VERSION 5.7 ;
  NOWIREEXTENSIONATPIN ON ;
  DIVIDERCHAR "/" ;
  BUSBITCHARS "[]" ;
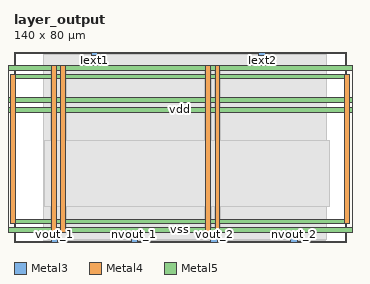
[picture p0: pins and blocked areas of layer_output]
MACRO layer_output
  CLASS BLOCK ;
  FOREIGN layer_output ;
  ORIGIN 0.000 0.000 ;
  SIZE 140.000 BY 80.000 ;
  PIN Iext1
    DIRECTION INPUT ;
    USE SIGNAL ;
    ANTENNAGATEAREA 0.280000 ;
    ANTENNADIFFAREA 1.380000 ;
    PORT
      LAYER Metal3 ;
        RECT 32.480 78.500 35.280 80.000 ;
    END
  END Iext1
  PIN Iext2
    DIRECTION INPUT ;
    USE SIGNAL ;
    ANTENNAGATEAREA 0.280000 ;
    ANTENNADIFFAREA 1.380000 ;
    PORT
      LAYER Metal3 ;
        RECT 103.040 78.500 105.840 80.000 ;
    END
  END Iext2
  PIN nvout_1
    DIRECTION OUTPUT ;
    USE SIGNAL ;
    ANTENNAGATEAREA 0.560000 ;
    ANTENNADIFFAREA 0.750000 ;
    PORT
      LAYER Metal3 ;
        RECT 49.280 0.000 52.080 1.500 ;
    END
  END nvout_1
  PIN nvout_2
    DIRECTION OUTPUT ;
    USE SIGNAL ;
    ANTENNAGATEAREA 0.560000 ;
    ANTENNADIFFAREA 0.750000 ;
    PORT
      LAYER Metal3 ;
        RECT 116.480 0.000 119.280 1.500 ;
    END
  END nvout_2
  PIN vdd
    DIRECTION INOUT ;
    USE POWER ;
    PORT
      LAYER Metal4 ;
        RECT -1.280 7.680 0.720 70.720 ;
    END
    PORT
      LAYER Metal4 ;
        RECT 139.280 7.680 141.280 70.720 ;
    END
    PORT
      LAYER Metal5 ;
        RECT -1.280 7.680 141.280 9.680 ;
    END
    PORT
      LAYER Metal5 ;
        RECT -1.280 68.720 141.280 70.720 ;
    END
    PORT
      LAYER Metal4 ;
        RECT 15.720 4.180 17.720 74.220 ;
    END
    PORT
      LAYER Metal4 ;
        RECT 80.720 4.180 82.720 74.220 ;
    END
    PORT
      LAYER Metal5 ;
        RECT -4.780 54.680 144.780 56.680 ;
    END
  END vdd
  PIN vout_1
    DIRECTION OUTPUT ;
    USE SIGNAL ;
    ANTENNADIFFAREA 0.750000 ;
    PORT
      LAYER Metal3 ;
        RECT 15.680 0.000 18.480 1.500 ;
    END
  END vout_1
  PIN vout_2
    DIRECTION OUTPUT ;
    USE SIGNAL ;
    ANTENNADIFFAREA 0.750000 ;
    PORT
      LAYER Metal3 ;
        RECT 82.880 0.000 85.680 1.500 ;
    END
  END vout_2
  PIN vss
    DIRECTION INOUT ;
    USE GROUND ;
    PORT
      LAYER Metal4 ;
        RECT -4.780 4.180 -2.780 74.220 ;
    END
    PORT
      LAYER Metal4 ;
        RECT 142.780 4.180 144.780 74.220 ;
    END
    PORT
      LAYER Metal5 ;
        RECT -4.780 4.180 144.780 6.180 ;
    END
    PORT
      LAYER Metal5 ;
        RECT -4.780 72.220 144.780 74.220 ;
    END
    PORT
      LAYER Metal4 ;
        RECT 19.720 4.180 21.720 74.220 ;
    END
    PORT
      LAYER Metal4 ;
        RECT 84.720 4.180 86.720 74.220 ;
    END
    PORT
      LAYER Metal5 ;
        RECT -4.780 58.680 144.780 60.680 ;
    END
  END vss
  OBS
      LAYER Nwell ;
        RECT 15.000 18.300 130.860 38.890 ;
      LAYER Metal1 ;
        RECT 15.190 18.510 130.630 38.680 ;
      LAYER Metal2 ;
        RECT 13.650 15.250 131.170 42.640 ;
      LAYER Metal3 ;
        RECT 12.410 78.200 32.180 78.820 ;
        RECT 35.580 78.200 102.740 78.820 ;
        RECT 106.140 78.200 131.170 78.820 ;
        RECT 12.410 1.800 131.170 78.200 ;
        RECT 12.410 0.700 15.380 1.800 ;
        RECT 18.780 0.700 48.980 1.800 ;
        RECT 52.380 0.700 82.580 1.800 ;
        RECT 85.980 0.700 116.180 1.800 ;
        RECT 119.580 0.700 131.170 1.800 ;
      LAYER Metal4 ;
        RECT 12.460 74.520 131.670 78.870 ;
        RECT 12.460 3.880 15.420 74.520 ;
        RECT 18.020 3.880 19.420 74.520 ;
        RECT 22.020 3.880 80.420 74.520 ;
        RECT 83.020 3.880 84.420 74.520 ;
        RECT 87.020 3.880 131.670 74.520 ;
        RECT 12.460 1.210 131.670 3.880 ;
      LAYER Metal5 ;
        RECT 13.000 15.000 132.860 42.890 ;
  END
END layer_output
END LIBRARY

